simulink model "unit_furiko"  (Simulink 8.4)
settings: Solver=ode45  StartTime=0.0  StopTime=10.0  MaxStep=1e-3  MinStep=1e-4  RelTol=1e-3
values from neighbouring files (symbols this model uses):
  g = 9.8    [dblfuriko.m]    (also in furiko.m)
  k = 9e9    (= 9000000000)    [ElectDipole.m]    (also in solvGasSei.m = 1; solvJacobi.m = 1; solvSOR.m = 1; solvSORerr.m = 1)
  m = 4*m    (= 4)    [romberg.m]
undefined symbols (not defined in the file or in its folder): l

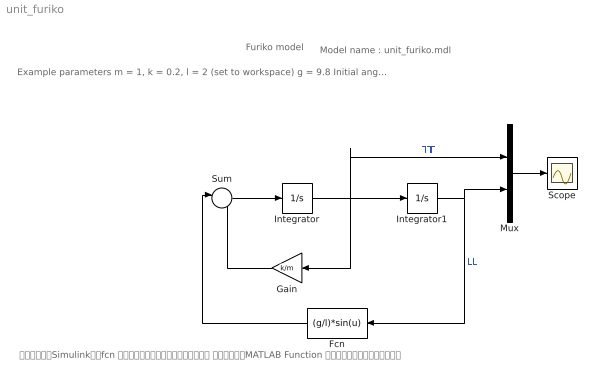
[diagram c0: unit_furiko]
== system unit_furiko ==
  note: 注意）最新のSimulinkではfcn ブロックの使用を推奨していません． したがって，MATLAB Function ブロックに変更してください．
  note: Model name : unit_furiko.mdl
  note: Example parameters m = 1, k = 0.2, l = 2 (set to workspace) g = 9.8 Initial angle : 1 rad (set to integrator1 block)
  note: Furiko model
  Fcn : Fcn  Expr=(g/l)*sin(u)
  Gain : Gain  Gain=k/m
  Integrator : Integrator
  Integrator1 : Integrator  InitialCondition=1
  Mux : Mux  Inputs=2
  Scope : Scope
  Sum : Sum  Inputs=|--
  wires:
  Fcn/1 -> Sum/1
  Gain/1 -> Sum/2
  Sum/1 -> Integrator/1
  Integrator/1 -> Mux/1, Gain/1, Integrator1/1  "角速度"
  Integrator1/1 -> Mux/2, Fcn/1  "角度"
  Mux/1 -> Scope/1
